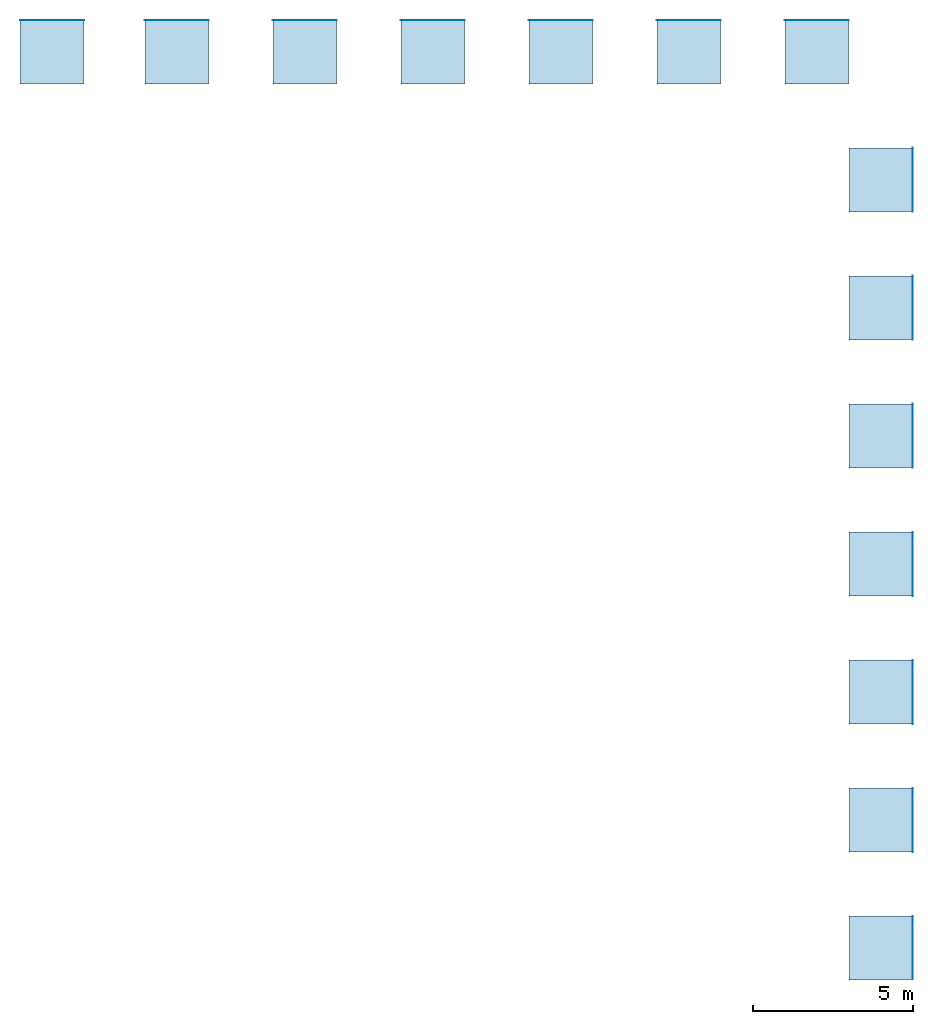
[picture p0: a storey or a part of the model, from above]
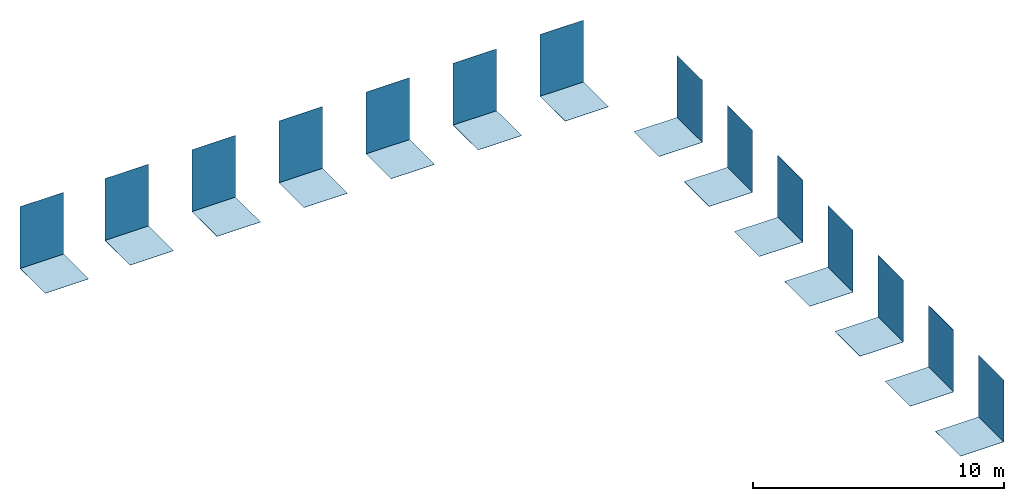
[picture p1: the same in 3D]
Properties of the parts of a building model (IFC2X3)

# File
Description: ViewDefinition [CoordinationView_V2.0]
File name: Project Number
Time: 2019-05-09T15:24:18
Written by: The EXPRESS Data Manager Version 5.02.0100.07 : 28 Aug 2013
Made in: 20181011_1645(x64) - Exporter 17.2.0.0 - Alternate UI 17.2.0.0
Comment: STEP Physical File produced by: The EXPRESS Data Manager Version 5.02.0100.07 : 28 Aug 2013 * Module: EDMstepFileFactory/EDMstandAlone * Creation date: Thu May 09 15:24:18 2019 * Host: aiepmoliner * Database: C:\Users\ES0050~1\AppData\Local\Temp\{F7FDD86A-AAB0-48F5-83BF-313EA6CE89DC}\ifc * Database version: 5507 * Database creation date: Thu May 09 15:24:14 2019 * Schema: IFC2X3 * Model: DataRepository.ifc * Model creation date: Thu May 09 15:24:15 2019 * Header model: DataRepository.ifc_HeaderModel * Header model creation date: Thu May 09 15:24:15 2019 * EDMuser: sdai-user * EDMgroup: sdai-group * License ID and type: 5605 : Permanent license. Expiry date: * EDMstepFileFactory options: 020000

# IfcProject, Project Number
LongName: Project Name; Phase: Project Status

# IfcSite, Default
RefLatitude: 42, 21, 31, 181945; RefLongitude: -71, -3, -24, -263305; RefElevation: 0 mm

# IfcBuildingStorey, Level 1
LongName: Level 1; Elevation: 0 mm

# IfcSlab: Floor:PGR_AnticColonial_WoodFibreBoards_Residence_Arizona-193x1380mm-100201388, Floor:PGR_AnticColonial_WoodFibreBoards_Residence_Arizona-193x1380mm-100201388:211493
In: Level 1
PredefinedType: FLOOR; Material: PGR_AnticColonial_WoodFibreBoards_Residence_Arizona-193x1380mm-100201388 8 mm

# IfcSlab: Floor:PGR_AnticColonial_WoodFibreBoards_Residence_Idaho-193x1380mm-100201389, Floor:PGR_AnticColonial_WoodFibreBoards_Residence_Idaho-193x1380mm-100201389:211503
In: Level 1
PredefinedType: FLOOR; Material: PGR_AnticColonial_WoodFibreBoards_Residence_Idaho-193x1380mm-100201389 8 mm

# IfcSlab: Floor:PGR_AnticColonial_WoodFibreBoards_Residence_Iowa-193x1380mm-100176300, Floor:PGR_AnticColonial_WoodFibreBoards_Residence_Iowa-193x1380mm-100176300:211553
In: Level 1
PredefinedType: FLOOR; Material: PGR_AnticColonial_WoodFibreBoards_Residence_Iowa-193x1380mm-100176300 8 mm

# IfcSlab: Floor:PGR_AnticColonial_WoodFibreBoards_Residence_Maine-193x1380mm-100176301, Floor:PGR_AnticColonial_WoodFibreBoards_Residence_Maine-193x1380mm-100176301:214856
In: Level 1
PredefinedType: FLOOR; Material: PGR_AnticColonial_WoodFibreBoards_Residence_Maine-193x1380mm-100176301 8 mm

# IfcSlab: Floor:PGR_AnticColonial_WoodFibreBoards_Residence_Misuri-193x1380mm-100201397, Floor:PGR_AnticColonial_WoodFibreBoards_Residence_Misuri-193x1380mm-100201397:211513
In: Level 1
PredefinedType: FLOOR; Material: PGR_AnticColonial_WoodFibreBoards_Residence_Misuri-193x1380mm-100201397 8 mm

# IfcSlab: Floor:PGR_AnticColonial_WoodFibreBoards_Residence_Nevada-193x1380mm-100201404, Floor:PGR_AnticColonial_WoodFibreBoards_Residence_Nevada-193x1380mm-100201404:211603
In: Level 1
PredefinedType: FLOOR; Material: PGR_AnticColonial_WoodFibreBoards_Residence_Nevada-193x1380mm-100201404 8 mm

# IfcSlab: Floor:PGR_AnticColonial_WoodFibreBoards_Residence_New_Jersey-193x1380mm-100176290, Floor:PGR_AnticColonial_WoodFibreBoards_Residence_New_Jersey-193x1380mm-100176290:211543
In: Level 1
PredefinedType: FLOOR; Material: PGR_AnticColonial_WoodFibreBoards_Residence_New_Jersey-193x1380mm-100176290 8 mm

# IfcSlab: Floor:PGR_AnticColonial_WoodFibreBoards_Residence_Nogal-193x1380mm-100202966, Floor:PGR_AnticColonial_WoodFibreBoards_Residence_Nogal-193x1380mm-100202966:211523
In: Level 1
PredefinedType: FLOOR; Material: PGR_AnticColonial_WoodFibreBoards_Residence_Nogal-193x1380mm-100202966 8 mm

# IfcSlab: Floor:PGR_AnticColonial_WoodFibreBoards_Residence_Ohio-193x1380mm-100175399, Floor:PGR_AnticColonial_WoodFibreBoards_Residence_Ohio-193x1380mm-100175399:211593
In: Level 1
PredefinedType: FLOOR; Material: PGR_AnticColonial_WoodFibreBoards_Residence_Ohio-193x1380mm-100175399 8 mm

# IfcSlab: Floor:PGR_AnticColonial_WoodFibreBoards_Residence_Roble-193x1380mm-100176291, Floor:PGR_AnticColonial_WoodFibreBoards_Residence_Roble-193x1380mm-100176291:211563
In: Level 1
PredefinedType: FLOOR; Material: PGR_AnticColonial_WoodFibreBoards_Residence_Roble-193x1380mm-100176291 8 mm

# IfcSlab: Floor:PGR_AnticColonial_WoodFibreBoards_Residence_Roble_Decape-193x1380mm-100176288, Floor:PGR_AnticColonial_WoodFibreBoards_Residence_Roble_Decape-193x1380mm-100176288:202324
In: Level 1
PredefinedType: FLOOR; Material: PGR_AnticColonial_WoodFibreBoards_Residence_Roble_Decape-193x1380mm-100176288 8 mm

# IfcSlab: Floor:PGR_AnticColonial_WoodFibreBoards_Residence_Utah-193x1380mm-100201410, Floor:PGR_AnticColonial_WoodFibreBoards_Residence_Utah-193x1380mm-100201410:211533
In: Level 1
PredefinedType: FLOOR; Material: PGR_AnticColonial_WoodFibreBoards_Residence_Utah-193x1380mm-100201410 8 mm

# IfcSlab: Floor:PGR_AnticColonial_WoodFibreBoards_Residence_Vermont-193x1380mm-100176289, Floor:PGR_AnticColonial_WoodFibreBoards_Residence_Vermont-193x1380mm-100176289:211573
In: Level 1
PredefinedType: FLOOR; Material: PGR_AnticColonial_WoodFibreBoards_Residence_Vermont-193x1380mm-100176289 8 mm

# IfcSlab: Floor:PGR_AnticColonial_WoodFibreBoards_Residence_Virginia-193x1380mm-100175398, Floor:PGR_AnticColonial_WoodFibreBoards_Residence_Virginia-193x1380mm-100175398:211583
In: Level 1
PredefinedType: FLOOR; Material: PGR_AnticColonial_WoodFibreBoards_Residence_Virginia-193x1380mm-100175398 8 mm

# IfcWallStandardCase: Basic Wall:PGR_AnticColonial_WoodFibreBoards_Residence_Arizona-193x1380mm-100201388, Basic Wall:PGR_AnticColonial_WoodFibreBoards_Residence_Arizona-193x1380mm-100201388:211498
In: Level 1
Type - PredefinedType: STANDARD; Material: PGR_AnticColonial_WoodFibreBoards_Residence_Arizona-193x1380mm-100201388 8 mm
Type - NBS_General - Author: Porcelanosa Group; BIMObjectName: PGR_AnticColonial_WoodFibreBoards_Residence_Arizona_193x1380mm-100201388; ManufacturerURL: www.anticcolonial.com; NBSDescription: Wood laminate strips and boards; NBSReference: 45-45-95/370; ProductInformation: http://calidad.info-grupo.com:8081/GeneraFicha3/PDF?articulo=100201388&lang=EN&un=0; Revision: n/a; Uniclass2015Code: Pr_25_71_97_92; Uniclass2015Title: Wood fibre boards; Uniclass2015Version: V1_9; Version: 1
Type - COBie - AccessibilityPerformance: See ProductInformation for technical PDF; AssetType: Fixed; Category: Walls; CodePerformance: FSC; Color: Gray; Constituents: n/a; Description: Laminate flooring, RESIDENCE collection from L'ANTIC COLONIAL (Porcelanosa Group), ROBLE DECAPE model and LIFE finish, 19,3x138 cm. (8mm thickness), Class 23/32, abrasion resistance AC4, formed by high density fiber board and water-repellent glues.; DurationUnit: year; ExpectedLife: n/a; Features: See ProductInformation for technical PDF; Grade: n/a; Manufacturer: bim.gp@porcelanosagrupo.com; ModelNumber: 100201388; ModelReference: AC4 RESIDENCE 1L ARIZONA 19,3X138X0,8; Name: WoodFibreBoards_Residence_Arizona_193x1380mm-100201388; ReplacementCost: n/a; Shape: Rectangular; Size: 193x1380x8mm; Sustainability Performance: See ProductInformation for technical PDF; WarrantyDescription: Manufacturer warranty, applicable worldwide, with the pertinent national legislation prevailing in all cases; all products must have been manufactured and fitted in accordance with the Fabricator's Manual, and have been used and cared for in accordance with the Guide to Use, Cleaning and Care available on the web page www.porcelanosa.com; WarrantyDurationLabor: n/a; WarrantyDurationParts: 20; WarrantyDurationUnit: year; WarrantyGuarantorLabor: n/a; WarrantyGuarantorParts: bim.gp@porcelanosagrupo.com
Type - Pset_CoveringCommon - IsExternal: no; Reference: -; AcousticRating: n/a; Finish: Life; FireRating: Cfl-s1; FlammabilityRating: n/a; FragilityRating: n/a; Material: High-density fibreboard; SurfaceSpreadOfFlame: n/a; ThermalTransmittance: 287.5 kg/K/s3; TotalThickness: 8 mm
Type - IFC - IfcExportAS: IfcCoveringType; IfcExportType: Flooring
Type - NBS_Data - AbrasionResistance: AC4; Collection: Residence; CreationDate: 2018/09; SlipResistanceValuePendulumTestValue: Class DS; StainResistance: Grade 5 (G 1 and 2) and Grade 4 (G 3)
COBie - AssetIdentifier: n/a; BarCode: n/a; InstallationDate: 1900-12-31T23:59:59; TagNumber: n/a; WarrantyStartDate: 1900-12-31T23:59:59

# IfcWallStandardCase: Basic Wall:PGR_AnticColonial_WoodFibreBoards_Residence_Idaho-193x1380mm-100201389, Basic Wall:PGR_AnticColonial_WoodFibreBoards_Residence_Idaho-193x1380mm-100201389:211508
In: Level 1
Type - PredefinedType: STANDARD; Material: PGR_AnticColonial_WoodFibreBoards_Residence_Idaho-193x1380mm-100201389 8 mm
Type - NBS_General - Author: Porcelanosa Group; BIMObjectName: PGR_AnticColonial_WoodFibreBoards_Residence_Idaho_193x1380mm-100201389; ManufacturerURL: www.anticcolonial.com; NBSDescription: Wood laminate strips and boards; NBSReference: 45-45-95/370; ProductInformation: http://calidad.info-grupo.com:8081/GeneraFicha3/PDF?articulo=100201389&lang=EN&un=0; Revision: n/a; Uniclass2015Code: Pr_25_71_97_92; Uniclass2015Title: Wood fibre boards; Uniclass2015Version: V1_9; Version: 1
Type - COBie - AccessibilityPerformance: See ProductInformation for technical PDF; AssetType: Fixed; Category: Walls; CodePerformance: FSC; Color: Brown; Constituents: n/a; Description: Laminate flooring, RESIDENCE collection from L'ANTIC COLONIAL (Porcelanosa Group), ROBLE DECAPE model and LIFE finish, 19,3x138 cm. (8mm thickness), Class 23/32, abrasion resistance AC4, formed by high density fiber board and water-repellent glues.; DurationUnit: year; ExpectedLife: n/a; Features: See ProductInformation for technical PDF; Grade: n/a; Manufacturer: bim.gp@porcelanosagrupo.com; ModelNumber: 100201389; ModelReference: AC4 RESIDENCE 1L IDAHO 19,3X138X0,8; Name: WoodFibreBoards_Residence_Idaho_193x1380mm-100201389; ReplacementCost: n/a; Shape: Rectangular; Size: 193x1380x8mm; Sustainability Performance: See ProductInformation for technical PDF; WarrantyDescription: Manufacturer warranty, applicable worldwide, with the pertinent national legislation prevailing in all cases; all products must have been manufactured and fitted in accordance with the Fabricator's Manual, and have been used and cared for in accordance with the Guide to Use, Cleaning and Care available on the web page www.porcelanosa.com; WarrantyDurationLabor: n/a; WarrantyDurationParts: 20; WarrantyDurationUnit: year; WarrantyGuarantorLabor: n/a; WarrantyGuarantorParts: bim.gp@porcelanosagrupo.com
Type - Pset_CoveringCommon - IsExternal: no; Reference: -; AcousticRating: n/a; Finish: Life; FireRating: Cfl-s1; FlammabilityRating: n/a; FragilityRating: n/a; Material: High-density fibreboard; SurfaceSpreadOfFlame: n/a; ThermalTransmittance: 287.5 kg/K/s3; TotalThickness: 8 mm
Type - IFC - IfcExportAS: IfcCoveringType; IfcExportType: Flooring
Type - NBS_Data - AbrasionResistance: AC4; Collection: Residence; CreationDate: 2018/09; SlipResistanceValuePendulumTestValue: Class DS; StainResistance: Grade 5 (G 1 and 2) and Grade 4 (G 3)
COBie - AssetIdentifier: n/a; BarCode: n/a; InstallationDate: 1900-12-31T23:59:59; TagNumber: n/a; WarrantyStartDate: 1900-12-31T23:59:59

# IfcWallStandardCase: Basic Wall:PGR_AnticColonial_WoodFibreBoards_Residence_Iowa-193x1380mm-100176300, Basic Wall:PGR_AnticColonial_WoodFibreBoards_Residence_Iowa-193x1380mm-100176300:211558
In: Level 1
Type - PredefinedType: STANDARD; Material: PGR_AnticColonial_WoodFibreBoards_Residence_Iowa-193x1380mm-100176300 8 mm
Type - NBS_General - Author: Porcelanosa Group; BIMObjectName: PGR_AnticColonial_WoodFibreBoards_Residence_Iowa_193x1380mm-100176300; ManufacturerURL: www.anticcolonial.com; NBSDescription: Wood laminate strips and boards; NBSReference: 45-45-95/370; ProductInformation: http://calidad.info-grupo.com:8081/GeneraFicha3/PDF?articulo=100176300&lang=EN&un=0; Revision: n/a; Uniclass2015Code: Pr_25_71_97_92; Uniclass2015Title: Wood fibre boards; Uniclass2015Version: V1_9; Version: 1
Type - COBie - AccessibilityPerformance: See ProductInformation for technical PDF; AssetType: Fixed; Category: Walls; CodePerformance: FSC; Color: Walnut; Constituents: n/a; Description: Laminate flooring, RESIDENCE collection from L'ANTIC COLONIAL (Porcelanosa Group), ROBLE DECAPE model and LIFE finish, 19,3x138 cm. (8mm thickness), Class 23/32, abrasion resistance AC4, formed by high density fiber board and water-repellent glues.; DurationUnit: year; ExpectedLife: n/a; Features: See ProductInformation for technical PDF; Grade: n/a; Manufacturer: bim.gp@porcelanosagrupo.com; ModelNumber: 100176300; ModelReference: AC4 RESIDENCE ANTI 2L IOWA 19,3X138X0,8; Name: WoodFibreBoards_Residence_Iowa_193x1380mm-100176300; ReplacementCost: n/a; Shape: Rectangular; Size: 193x1380x8mm; Sustainability Performance: See ProductInformation for technical PDF; WarrantyDescription: Manufacturer warranty, applicable worldwide, with the pertinent national legislation prevailing in all cases; all products must have been manufactured and fitted in accordance with the Fabricator's Manual, and have been used and cared for in accordance with the Guide to Use, Cleaning and Care available on the web page www.porcelanosa.com; WarrantyDurationLabor: n/a; WarrantyDurationParts: 20; WarrantyDurationUnit: year; WarrantyGuarantorLabor: n/a; WarrantyGuarantorParts: bim.gp@porcelanosagrupo.com
Type - Pset_CoveringCommon - IsExternal: no; Reference: -; AcousticRating: n/a; Finish: Life; FireRating: Cfl-s1; FlammabilityRating: n/a; FragilityRating: n/a; Material: High-density fibreboard; SurfaceSpreadOfFlame: n/a; ThermalTransmittance: 287.5 kg/K/s3; TotalThickness: 8 mm
Type - IFC - IfcExportAS: IfcCoveringType; IfcExportType: Flooring
Type - NBS_Data - AbrasionResistance: AC4; Collection: Residence; CreationDate: 2018/09; SlipResistanceValuePendulumTestValue: Class DS; StainResistance: Grade 5 (G 1 and 2) and Grade 4 (G 3)
COBie - AssetIdentifier: n/a; BarCode: n/a; InstallationDate: 1900-12-31T23:59:59; TagNumber: n/a; WarrantyStartDate: 1900-12-31T23:59:59

# IfcWallStandardCase: Basic Wall:PGR_AnticColonial_WoodFibreBoards_Residence_Maine-193x1380mm-100176301, Basic Wall:PGR_AnticColonial_WoodFibreBoards_Residence_Maine-193x1380mm-100176301:214861
In: Level 1
Type - PredefinedType: STANDARD; Material: PGR_AnticColonial_WoodFibreBoards_Residence_Maine-193x1380mm-100176301 8 mm
Type - NBS_General - Author: Porcelanosa Group; BIMObjectName: PGR_AnticColonial_WoodFibreBoards_Residence_Maine_193x1380mm-100201404; ManufacturerURL: www.anticcolonial.com; NBSDescription: Wood laminate strips and boards; NBSReference: 45-45-95/370; ProductInformation: http://calidad.info-grupo.com:8081/GeneraFicha3/PDF?articulo=100176301&lang=EN&un=0; Revision: n/a; Uniclass2015Code: Pr_25_71_97_92; Uniclass2015Title: Wood fibre boards; Uniclass2015Version: V1_9; Version: 1
Type - COBie - AccessibilityPerformance: See ProductInformation for technical PDF; AssetType: Fixed; Category: Pr_25_71_97_92: Wood Fibre Boards; CodePerformance: FSC; Color: Natural; Constituents: n/a; Description: Laminate flooring, RESIDENCE collection from L'ANTIC COLONIAL (Porcelanosa Group), ROBLE DECAPE model and LIFE finish, 19,3x138 cm. (8mm thickness), Class 23/32, abrasion resistance AC4, formed by high density fiber board and water-repellent glues.; DurationUnit: year; ExpectedLife: n/a; Features: See ProductInformation for technical PDF; Grade: n/a; Manufacturer: bim.gp@porcelanosagrupo.com; ModelNumber: 100176301; ModelReference: AC4 RESIDENCE 2L MAINE 19,3X138X0,8; Name: WoodFibreBoards_Residence_Maine_193x1380mm-100201404; ReplacementCost: n/a; Shape: Rectangular; Size: 193x1380x8mm; Sustainability Performance: See ProductInformation for technical PDF; WarrantyDescription: Manufacturer warranty, applicable worldwide, with the pertinent national legislation prevailing in all cases; all products must have been manufactured and fitted in accordance with the Fabricator's Manual, and have been used and cared for in accordance with the Guide to Use, Cleaning and Care available on the web page www.porcelanosa.com; WarrantyDurationLabor: n/a; WarrantyDurationParts: 20; WarrantyDurationUnit: year; WarrantyGuarantorLabor: n/a; WarrantyGuarantorParts: bim.gp@porcelanosagrupo.com
Type - Pset_CoveringCommon - IsExternal: no; Reference: -; AcousticRating: n/a; Finish: Life; FireRating: Cfl-s1; FlammabilityRating: n/a; FragilityRating: n/a; Material: High-density fibreboard; SurfaceSpreadOfFlame: n/a; ThermalTransmittance: 287.5 kg/K/s3; TotalThickness: 8 mm
Type - IFC - IfcExportAS: IfcCoveringType; IfcExportType: Flooring
Type - NBS_Data - AbrasionResistance: AC4; Collection: Residence; CreationDate: 2019/05; SlipResistanceValuePendulumTestValue: Class DS; StainResistance: Grade 5 (G 1 and 2) and Grade 4 (G 3)
COBie - AssetIdentifier: n/a; BarCode: n/a; InstallationDate: 1900-12-31T23:59:59; TagNumber: n/a; WarrantyStartDate: 1900-12-31T23:59:59

# IfcWallStandardCase: Basic Wall:PGR_AnticColonial_WoodFibreBoards_Residence_Misuri-193x1380mm-100201397 (2)
In: Level 1
Type - PredefinedType: STANDARD; Material: PGR_AnticColonial_WoodFibreBoards_Residence_Misuri-193x1380mm-100201397 8 mm
Type - NBS_General - Author: Porcelanosa Group; BIMObjectName: PGR_AnticColonial_WoodFibreBoards_Residence_Nevada_193x1380mm-100201404; ManufacturerURL: www.anticcolonial.com; NBSDescription: Wood laminate strips and boards; NBSReference: 45-45-95/370; ProductInformation: http://calidad.info-grupo.com:8081/GeneraFicha3/PDF?articulo=100201404&lang=EN&un=0; Revision: n/a; Uniclass2015Code: Pr_25_71_97_92; Uniclass2015Title: Wood fibre boards; Uniclass2015Version: V1_9; Version: 1
Type - COBie - AccessibilityPerformance: See ProductInformation for technical PDF; AssetType: Fixed; Category: Pr_25_71_97_92: Wood Fibre Boards; CodePerformance: FSC; Color: Brown; Constituents: n/a; Description: Laminate flooring, RESIDENCE collection from L'ANTIC COLONIAL (Porcelanosa Group), ROBLE DECAPE model and LIFE finish, 19,3x138 cm. (8mm thickness), Class 23/32, abrasion resistance AC4, formed by high density fiber board and water-repellent glues.; DurationUnit: year; ExpectedLife: n/a; Features: See ProductInformation for technical PDF; Grade: n/a; Manufacturer: bim.gp@porcelanosagrupo.com; ModelNumber: 100201404; ModelReference: AC4 RESIDENCE 1L NEVADA 19,3X138X0,8; Name: WoodFibreBoards_Residence_Nevada_193x1380mm-100201404; ReplacementCost: n/a; Shape: Rectangular; Size: 193x1380x8mm; Sustainability Performance: See ProductInformation for technical PDF; WarrantyDescription: Manufacturer warranty, applicable worldwide, with the pertinent national legislation prevailing in all cases; all products must have been manufactured and fitted in accordance with the Fabricator's Manual, and have been used and cared for in accordance with the Guide to Use, Cleaning and Care available on the web page www.porcelanosa.com; WarrantyDurationLabor: n/a; WarrantyDurationParts: 20; WarrantyDurationUnit: year; WarrantyGuarantorLabor: n/a; WarrantyGuarantorParts: bim.gp@porcelanosagrupo.com
Type - Pset_CoveringCommon - IsExternal: no; Reference: -; AcousticRating: n/a; Finish: Life; FireRating: Cfl-s1; FlammabilityRating: n/a; FragilityRating: n/a; Material: High-density fibreboard; SurfaceSpreadOfFlame: n/a; ThermalTransmittance: 287.5 kg/K/s3; TotalThickness: 8 mm
Type - IFC - IfcExportAS: IfcCoveringType; IfcExportType: Flooring
Type - NBS_Data - AbrasionResistance: AC4; Collection: Residence; CreationDate: 2018/09; SlipResistanceValuePendulumTestValue: Class DS; StainResistance: Grade 5 (G 1 and 2) and Grade 4 (G 3)
COBie - AssetIdentifier: n/a; BarCode: n/a; InstallationDate: 1900-12-31T23:59:59; TagNumber: n/a; WarrantyStartDate: 1900-12-31T23:59:59
Name (Basic Wall:PGR_AnticColonial_WoodFibreBoards_Residence_Misuri-193x1380mm-100201397:...)
211518
212001

# IfcWallStandardCase: Basic Wall:PGR_AnticColonial_WoodFibreBoards_Residence_Nevada-193x1380mm-100201404, Basic Wall:PGR_AnticColonial_WoodFibreBoards_Residence_Nevada-193x1380mm-100201404:211608
In: Level 1
Type - PredefinedType: STANDARD; Material: PGR_AnticColonial_WoodFibreBoards_Residence_Nevada-193x1380mm-100201404 8 mm
Type - NBS_General - Author: Porcelanosa Group; BIMObjectName: PGR_AnticColonial_WoodFibreBoards_Residence_Utah_193x1380mm-100201410; ManufacturerURL: www.anticcolonial.com; NBSDescription: Wood laminate strips and boards; NBSReference: 45-45-95/370; ProductInformation: http://calidad.info-grupo.com:8081/GeneraFicha3/PDF?articulo=100201410&lang=EN&un=0; Revision: n/a; Uniclass2015Code: Pr_25_71_97_92; Uniclass2015Title: Wood fibre boards; Uniclass2015Version: V1_9; Version: 1
Type - COBie - AccessibilityPerformance: See ProductInformation for technical PDF; AssetType: Fixed; Category: Pr_25_71_97_92: Wood Fibre Boards; CodePerformance: FSC; Color: Brown; Constituents: n/a; Description: Laminate flooring, RESIDENCE collection from L'ANTIC COLONIAL (Porcelanosa Group), ROBLE DECAPE model and LIFE finish, 19,3x138 cm. (8mm thickness), Class 23/32, abrasion resistance AC4, formed by high density fiber board and water-repellent glues.; DurationUnit: year; ExpectedLife: n/a; Features: See ProductInformation for technical PDF; Grade: n/a; Manufacturer: bim.gp@porcelanosagrupo.com; ModelNumber: 100201410; ModelReference: AC4 RESIDENCE 1L UTAH 19,3X138X0,8; Name: WoodFibreBoards_Residence_Utah_193x1380mm-100201410; ReplacementCost: n/a; Shape: Rectangular; Size: 193x1380x8mm; Sustainability Performance: See ProductInformation for technical PDF; WarrantyDescription: Manufacturer warranty, applicable worldwide, with the pertinent national legislation prevailing in all cases; all products must have been manufactured and fitted in accordance with the Fabricator's Manual, and have been used and cared for in accordance with the Guide to Use, Cleaning and Care available on the web page www.porcelanosa.com; WarrantyDurationLabor: n/a; WarrantyDurationParts: 20; WarrantyDurationUnit: year; WarrantyGuarantorLabor: n/a; WarrantyGuarantorParts: bim.gp@porcelanosagrupo.com
Type - Pset_CoveringCommon - IsExternal: no; Reference: -; AcousticRating: n/a; Finish: Life; FireRating: Cfl-s1; FlammabilityRating: n/a; FragilityRating: n/a; Material: High-density fibreboard; SurfaceSpreadOfFlame: n/a; ThermalTransmittance: 287.5 kg/K/s3; TotalThickness: 8 mm
Type - IFC - IfcExportAS: IfcCoveringType; IfcExportType: Flooring
Type - NBS_Data - AbrasionResistance: AC4; Collection: Residence; CreationDate: 2018/09; SlipResistanceValuePendulumTestValue: Class DS; StainResistance: Grade 5 (G 1 and 2) and Grade 4 (G 3)
COBie - AssetIdentifier: n/a; BarCode: n/a; InstallationDate: 1900-12-31T23:59:59; TagNumber: n/a; WarrantyStartDate: 1900-12-31T23:59:59

# IfcWallStandardCase: Basic Wall:PGR_AnticColonial_WoodFibreBoards_Residence_New_Jersey-193x1380mm-100176290, Basic Wall:PGR_AnticColonial_WoodFibreBoards_Residence_New_Jersey-193x1380mm-100176290:211548
In: Level 1
Type - PredefinedType: STANDARD; Material: PGR_AnticColonial_WoodFibreBoards_Residence_New_Jersey-193x1380mm-100176290 8 mm
Type - NBS_General - Author: Porcelanosa Group; BIMObjectName: PGR_AnticColonial_WoodFibreBoards_Residence_NewJersey_193x1380mm-100176290; ManufacturerURL: www.anticcolonial.com; NBSDescription: Wood laminate strips and boards; NBSReference: 45-45-95/370; ProductInformation: http://calidad.info-grupo.com:8081/GeneraFicha3/PDF?articulo=100176290&lang=EN&un=0; Revision: n/a; Uniclass2015Code: Pr_25_71_97_92; Uniclass2015Title: Wood fibre boards; Uniclass2015Version: V1_9; Version: 1
Type - COBie - AccessibilityPerformance: See ProductInformation for technical PDF; AssetType: Fixed; Category: Pr_25_71_97_92: Wood Fibre Boards; CodePerformance: FSC; Color: Brown; Constituents: n/a; Description: Laminate flooring, RESIDENCE collection from L'ANTIC COLONIAL (Porcelanosa Group), ROBLE DECAPE model and LIFE finish, 19,3x138 cm. (8mm thickness), Class 23/32, abrasion resistance AC4, formed by high density fiber board and water-repellent glues.; DurationUnit: year; ExpectedLife: n/a; Features: See ProductInformation for technical PDF; Grade: n/a; Manufacturer: bim.gp@porcelanosagrupo.com; ModelNumber: 100176290; ModelReference: AC4 RESIDENCE ANTI 1L NEW JERSEY 19,3X138X0,8; Name: WoodFibreBoards_Residence_NewJersey_193x1380mm-100176290; ReplacementCost: n/a; Shape: Rectangular; Size: 193x1380x8mm; Sustainability Performance: See ProductInformation for technical PDF; WarrantyDescription: Manufacturer warranty, applicable worldwide, with the pertinent national legislation prevailing in all cases; all products must have been manufactured and fitted in accordance with the Fabricator's Manual, and have been used and cared for in accordance with the Guide to Use, Cleaning and Care available on the web page www.porcelanosa.com; WarrantyDurationLabor: n/a; WarrantyDurationParts: 20; WarrantyDurationUnit: year; WarrantyGuarantorLabor: n/a; WarrantyGuarantorParts: bim.gp@porcelanosagrupo.com
Type - Pset_CoveringCommon - IsExternal: no; Reference: -; AcousticRating: n/a; Finish: Life; FireRating: Cfl-s1; FlammabilityRating: n/a; FragilityRating: n/a; Material: High-density fibreboard; SurfaceSpreadOfFlame: n/a; ThermalTransmittance: 287.5 kg/K/s3; TotalThickness: 8 mm
Type - IFC - IfcExportAS: IfcCoveringType; IfcExportType: Flooring
Type - NBS_Data - AbrasionResistance: AC4; Collection: Residence; CreationDate: 2018/09; SlipResistanceValuePendulumTestValue: Class DS; StainResistance: Grade 5 (G 1 and 2) and Grade 4 (G 3)
COBie - AssetIdentifier: n/a; BarCode: n/a; InstallationDate: 1900-12-31T23:59:59; TagNumber: n/a; WarrantyStartDate: 1900-12-31T23:59:59

# IfcWallStandardCase: Basic Wall:PGR_AnticColonial_WoodFibreBoards_Residence_Nogal-193x1380mm-100202966, Basic Wall:PGR_AnticColonial_WoodFibreBoards_Residence_Nogal-193x1380mm-100202966:211528
In: Level 1
Type - PredefinedType: STANDARD; Material: PGR_AnticColonial_WoodFibreBoards_Residence_Nogal-193x1380mm-100202966 8 mm
Type - NBS_General - Author: Porcelanosa Group; BIMObjectName: PGR_AnticColonial_WoodFibreBoards_Residence_Nogal_193x1380mm-100202966; ManufacturerURL: www.anticcolonial.com; NBSDescription: Wood laminate strips and boards; NBSReference: 45-45-95/370; ProductInformation: http://calidad.info-grupo.com:8081/GeneraFicha3/PDF?articulo=100202966&lang=EN&un=0; Revision: n/a; Uniclass2015Code: Pr_25_71_97_92; Uniclass2015Title: Wood fibre boards; Uniclass2015Version: V1_9; Version: 1
Type - COBie - AccessibilityPerformance: See ProductInformation for technical PDF; AssetType: Fixed; Category: Pr_25_71_97_92: Wood Fibre Boards; CodePerformance: FSC; Color: Walnut; Constituents: n/a; Description: Laminate flooring, RESIDENCE collection from L'ANTIC COLONIAL (Porcelanosa Group), ROBLE DECAPE model and LIFE finish, 19,3x138 cm. (8mm thickness), Class 23/32, abrasion resistance AC4, formed by high density fiber board and water-repellent glues.; DurationUnit: year; ExpectedLife: n/a; Features: See ProductInformation for technical PDF; Grade: n/a; Manufacturer: bim.gp@porcelanosagrupo.com; ModelNumber: 100202966; ModelReference: AC4 RESIDENCE ANTI 1L NOGAL 19,3X138X0,8; Name: WoodFibreBoards_Residence_Nogal_193x1380mm-100202966; ReplacementCost: n/a; Shape: Rectangular; Size: 193x1380x8mm; Sustainability Performance: See ProductInformation for technical PDF; WarrantyDescription: Manufacturer warranty, applicable worldwide, with the pertinent national legislation prevailing in all cases; all products must have been manufactured and fitted in accordance with the Fabricator's Manual, and have been used and cared for in accordance with the Guide to Use, Cleaning and Care available on the web page www.porcelanosa.com; WarrantyDurationLabor: n/a; WarrantyDurationParts: 20; WarrantyDurationUnit: year; WarrantyGuarantorLabor: n/a; WarrantyGuarantorParts: bim.gp@porcelanosagrupo.com
Type - Pset_CoveringCommon - IsExternal: no; Reference: -; AcousticRating: n/a; Finish: Life; FireRating: Cfl-s1; FlammabilityRating: n/a; FragilityRating: n/a; Material: High-density fibreboard; SurfaceSpreadOfFlame: n/a; ThermalTransmittance: 287.5 kg/K/s3; TotalThickness: 8 mm
Type - IFC - IfcExportAS: IfcCoveringType; IfcExportType: Flooring
Type - NBS_Data - AbrasionResistance: AC4; Collection: Residence; CreationDate: 2018/09; SlipResistanceValuePendulumTestValue: Class DS; StainResistance: Grade 5 (G 1 and 2) and Grade 4 (G 3)
COBie - AssetIdentifier: n/a; BarCode: n/a; InstallationDate: 1900-12-31T23:59:59; TagNumber: n/a; WarrantyStartDate: 1900-12-31T23:59:59

# IfcWallStandardCase: Basic Wall:PGR_AnticColonial_WoodFibreBoards_Residence_Ohio-193x1380mm-100175399, Basic Wall:PGR_AnticColonial_WoodFibreBoards_Residence_Ohio-193x1380mm-100175399:211598
In: Level 1
Type - PredefinedType: STANDARD; Material: PGR_AnticColonial_WoodFibreBoards_Residence_Ohio-193x1380mm-100175399 8 mm
Type - NBS_General - Author: Porcelanosa Group; BIMObjectName: PGR_AnticColonial_WoodFibreBoards_Residence_Ohio_193x1380mm-100175399; ManufacturerURL: www.anticcolonial.com; NBSDescription: Wood laminate strips and boards; NBSReference: 45-45-95/370; ProductInformation: http://calidad.info-grupo.com:8081/GeneraFicha3/PDF?articulo=100175399&lang=EN&un=0; Revision: n/a; Uniclass2015Code: Pr_25_71_97_92; Uniclass2015Title: Wood fibre boards; Uniclass2015Version: V1_9; Version: 1
Type - COBie - AccessibilityPerformance: See ProductInformation for technical PDF; AssetType: Fixed; Category: Pr_25_71_97_92: Wood Fibre Boards; CodePerformance: FSC; Color: Gray; Constituents: n/a; Description: Laminate flooring, RESIDENCE collection from L'ANTIC COLONIAL (Porcelanosa Group), ROBLE DECAPE model and NATURAL finish, 19,3x138 cm. (8mm thickness), Class 23/32, abrasion resistance AC4, formed by high density fiber board and water-repellent glues.; DurationUnit: year; ExpectedLife: n/a; Features: See ProductInformation for technical PDF; Grade: n/a; Manufacturer: bim.gp@porcelanosagrupo.com; ModelNumber: 100175399; ModelReference: AC4 RESIDENCE ANTI 3L OHIO 19,3X138X0,8; Name: WoodFibreBoards_Residence_Ohio_193x1380mm-100175399; ReplacementCost: n/a; Shape: Rectangular; Size: 193x1380x8mm; Sustainability Performance: See ProductInformation for technical PDF; WarrantyDescription: Manufacturer warranty, applicable worldwide, with the pertinent national legislation prevailing in all cases; all products must have been manufactured and fitted in accordance with the Fabricator's Manual, and have been used and cared for in accordance with the Guide to Use, Cleaning and Care available on the web page www.porcelanosa.com; WarrantyDurationLabor: n/a; WarrantyDurationParts: 20; WarrantyDurationUnit: year; WarrantyGuarantorLabor: n/a; WarrantyGuarantorParts: bim.gp@porcelanosagrupo.com
Type - Pset_CoveringCommon - IsExternal: no; Reference: -; AcousticRating: n/a; Finish: Natural; FireRating: Cfl-s1; FlammabilityRating: n/a; FragilityRating: n/a; Material: High-density fibreboard; SurfaceSpreadOfFlame: n/a; ThermalTransmittance: 287.5 kg/K/s3; TotalThickness: 8 mm
Type - IFC - IfcExportAS: IfcCoveringType; IfcExportType: Flooring
Type - NBS_Data - AbrasionResistance: AC4; Collection: Residence; CreationDate: 2018/09; SlipResistanceValuePendulumTestValue: Class DS; StainResistance: Grade 5 (G 1 and 2) and Grade 4 (G 3)
COBie - AssetIdentifier: n/a; BarCode: n/a; InstallationDate: 1900-12-31T23:59:59; TagNumber: n/a; WarrantyStartDate: 1900-12-31T23:59:59

# IfcWallStandardCase: Basic Wall:PGR_AnticColonial_WoodFibreBoards_Residence_Roble-193x1380mm-100176291, Basic Wall:PGR_AnticColonial_WoodFibreBoards_Residence_Roble-193x1380mm-100176291:211568
In: Level 1
Type - PredefinedType: STANDARD; Material: PGR_AnticColonial_WoodFibreBoards_Residence_Roble-193x1380mm-100176291 8 mm
Type - NBS_General - Author: Porcelanosa Group; BIMObjectName: PGR_AnticColonial_WoodFibreBoards_Residence_Roble_193x1380mm-100176291; ManufacturerURL: www.anticcolonial.com; NBSDescription: Wood laminate strips and boards; NBSReference: 45-45-95/370; ProductInformation: http://calidad.info-grupo.com:8081/GeneraFicha3/PDF?articulo=100176291&lang=EN&un=0; Revision: n/a; Uniclass2015Code: Pr_25_71_97_92; Uniclass2015Title: Wood fibre boards; Uniclass2015Version: V1_9; Version: 1
Type - COBie - AccessibilityPerformance: See ProductInformation for technical PDF; AssetType: Fixed; Category: Pr_25_71_97_92: Wood Fibre Boards; CodePerformance: FSC; Color: Natural; Constituents: n/a; Description: Laminate flooring, RESIDENCE collection from L'ANTIC COLONIAL (Porcelanosa Group), ROBLE DECAPE model and LIFE finish, 19,3x138 cm. (8mm thickness), Class 23/32, abrasion resistance AC4, formed by high density fiber board and water-repellent glues.; DurationUnit: year; ExpectedLife: n/a; Features: See ProductInformation for technical PDF; Grade: n/a; Manufacturer: bim.gp@porcelanosagrupo.com; ModelNumber: 100176291; ModelReference: AC4 RESIDENCE ANTI 1L ROBLE 19,3X138X0,8; Name: WoodFibreBoards_Residence_Roble_193x1380mm-100176291; ReplacementCost: n/a; Shape: Rectangular; Size: 193x1380x8mm; Sustainability Performance: See ProductInformation for technical PDF; WarrantyDescription: Manufacturer warranty, applicable worldwide, with the pertinent national legislation prevailing in all cases; all products must have been manufactured and fitted in accordance with the Fabricator's Manual, and have been used and cared for in accordance with the Guide to Use, Cleaning and Care available on the web page www.porcelanosa.com; WarrantyDurationLabor: n/a; WarrantyDurationParts: 20; WarrantyDurationUnit: year; WarrantyGuarantorLabor: n/a; WarrantyGuarantorParts: bim.gp@porcelanosagrupo.com
Type - Pset_CoveringCommon - IsExternal: no; Reference: -; AcousticRating: n/a; Finish: Life; FireRating: Cfl-s1; FlammabilityRating: n/a; FragilityRating: n/a; Material: High-density fibreboard; SurfaceSpreadOfFlame: n/a; ThermalTransmittance: 287.5 kg/K/s3; TotalThickness: 8 mm
Type - IFC - IfcExportAS: IfcCoveringType; IfcExportType: Flooring
Type - NBS_Data - AbrasionResistance: AC4; Collection: Residence; CreationDate: 2018/09; SlipResistanceValuePendulumTestValue: Class DS; StainResistance: Grade 5 (G 1 and 2) and Grade 4 (G 3)
COBie - AssetIdentifier: n/a; BarCode: n/a; InstallationDate: 1900-12-31T23:59:59; TagNumber: n/a; WarrantyStartDate: 1900-12-31T23:59:59

# IfcWallStandardCase: Basic Wall:PGR_AnticColonial_WoodFibreBoards_Residence_Roble_Decape-193x1380mm-100176288, Basic Wall:PGR_AnticColonial_WoodFibreBoards_Residence_Roble_Decape-193x1380mm-100176288:202329
In: Level 1
Type - PredefinedType: STANDARD; Material: PGR_AnticColonial_WoodFibreBoards_Residence_Roble_Decape-193x1380mm-100176288 8 mm
Type - NBS_General - Author: Porcelanosa Group; BIMObjectName: PGR_AnticColonial_WoodFibreBoards_Residence_RobleDecape_193x1380mm-100176288; ManufacturerURL: www.anticcolonial.com; NBSDescription: Wood laminate strips and boards; NBSReference: 45-45-95/370; ProductInformation: http://calidad.info-grupo.com:8081/GeneraFicha3/PDF?articulo=100176288&lang=EN&un=0; Revision: n/a; Uniclass2015Code: Pr_25_71_97_92; Uniclass2015Title: Wood fibre boards; Uniclass2015Version: V1_9; Version: 1
Type - COBie - AccessibilityPerformance: See ProductInformation for technical PDF; AssetType: Fixed; Category: Walls; CodePerformance: FSC; Color: Natural; Constituents: n/a; Description: Laminate flooring, RESIDENCE collection from L'ANTIC COLONIAL (Porcelanosa Group), ROBLE DECAPE model and LIFE finish, 19,3x138 cm. (8mm thickness), Class 23/32, abrasion resistance AC4, formed by high density fiber board and water-repellent glues.; DurationUnit: year; ExpectedLife: n/a; Features: See ProductInformation for technical PDF; Grade: n/a; Manufacturer: bim.gp@porcelanosagrupo.com; ModelNumber: 100176288; ModelReference: AC4 RESIDENCE ANTI 1L R. DECAPE 19,3X138X0,8; Name: WoodFibreBoards_Residence_RobleDecape_193x1380mm-100176288; ReplacementCost: n/a; Shape: Rectangular; Size: 193x1380x8mm; Sustainability Performance: See ProductInformation for technical PDF; WarrantyDescription: Manufacturer warranty, applicable worldwide, with the pertinent national legislation prevailing in all cases; all products must have been manufactured and fitted in accordance with the Fabricator's Manual, and have been used and cared for in accordance with the Guide to Use, Cleaning and Care available on the web page www.porcelanosa.com; WarrantyDurationLabor: n/a; WarrantyDurationParts: 20; WarrantyDurationUnit: year; WarrantyGuarantorLabor: n/a; WarrantyGuarantorParts: bim.gp@porcelanosagrupo.com
Type - Pset_CoveringCommon - AcousticRating: n/a; Finish: Life; FireRating: Cfl-s1; FlammabilityRating: n/a; FragilityRating: n/a; IsExternal: no; Material: High-density fibreboard; SurfaceSpreadOfFlame: n/a; ThermalTransmittance: 287.5 kg/K/s3; TotalThickness: 8 mm; Reference: -
Type - IFC - IfcExportAS: IfcCoveringType; IfcExportType: Flooring
Type - NBS_Data - AbrasionResistance: AC4; Collection: Residence; CreationDate: 2018/09; SlipResistanceValuePendulumTestValue: Class DS; StainResistance: Grade 5 (G 1 and 2) and Grade 4 (G 3)
COBie - AssetIdentifier: n/a; BarCode: n/a; InstallationDate: 1900-12-31T23:59:59; TagNumber: n/a; WarrantyStartDate: 1900-12-31T23:59:59

# IfcWallStandardCase: Basic Wall:PGR_AnticColonial_WoodFibreBoards_Residence_Utah-193x1380mm-100201410, Basic Wall:PGR_AnticColonial_WoodFibreBoards_Residence_Utah-193x1380mm-100201410:211538
In: Level 1
Type - PredefinedType: STANDARD; Material: PGR_AnticColonial_WoodFibreBoards_Residence_Utah-193x1380mm-100201410 8 mm
Type - NBS_General - Author: Porcelanosa Group; BIMObjectName: PGR_AnticColonial_WoodFibreBoards_Residence_Nogal_193x1380mm-100202966; ManufacturerURL: www.anticcolonial.com; NBSDescription: Wood laminate strips and boards; NBSReference: 45-45-95/370; ProductInformation: http://calidad.info-grupo.com:8081/GeneraFicha3/PDF?articulo=100202966&lang=EN&un=0; Revision: n/a; Uniclass2015Code: Pr_25_71_97_92; Uniclass2015Title: Wood fibre boards; Uniclass2015Version: V1_9; Version: 1
Type - COBie - AccessibilityPerformance: See ProductInformation for technical PDF; AssetType: Fixed; Category: Pr_25_71_97_92: Wood Fibre Boards; CodePerformance: FSC; Color: Walnut; Constituents: n/a; Description: Laminate flooring, RESIDENCE collection from L'ANTIC COLONIAL (Porcelanosa Group), ROBLE DECAPE model and LIFE finish, 19,3x138 cm. (8mm thickness), Class 23/32, abrasion resistance AC4, formed by high density fiber board and water-repellent glues.; DurationUnit: year; ExpectedLife: n/a; Features: See ProductInformation for technical PDF; Grade: n/a; Manufacturer: bim.gp@porcelanosagrupo.com; ModelNumber: 100202966; ModelReference: AC4 RESIDENCE ANTI 1L NOGAL 19,3X138X0,8; Name: WoodFibreBoards_Residence_Nogal_193x1380mm-100202966; ReplacementCost: n/a; Shape: Rectangular; Size: 193x1380x8mm; Sustainability Performance: See ProductInformation for technical PDF; WarrantyDescription: Manufacturer warranty, applicable worldwide, with the pertinent national legislation prevailing in all cases; all products must have been manufactured and fitted in accordance with the Fabricator's Manual, and have been used and cared for in accordance with the Guide to Use, Cleaning and Care available on the web page www.porcelanosa.com; WarrantyDurationLabor: n/a; WarrantyDurationParts: 20; WarrantyDurationUnit: year; WarrantyGuarantorLabor: n/a; WarrantyGuarantorParts: bim.gp@porcelanosagrupo.com
Type - Pset_CoveringCommon - IsExternal: no; Reference: -; AcousticRating: n/a; Finish: Life; FireRating: Cfl-s1; FlammabilityRating: n/a; FragilityRating: n/a; Material: High-density fibreboard; SurfaceSpreadOfFlame: n/a; ThermalTransmittance: 287.5 kg/K/s3; TotalThickness: 8 mm
Type - IFC - IfcExportAS: IfcCoveringType; IfcExportType: Flooring
Type - NBS_Data - AbrasionResistance: AC4; Collection: Residence; CreationDate: 2018/09; SlipResistanceValuePendulumTestValue: Class DS; StainResistance: Grade 5 (G 1 and 2) and Grade 4 (G 3)
COBie - AssetIdentifier: n/a; BarCode: n/a; InstallationDate: 1900-12-31T23:59:59; TagNumber: n/a; WarrantyStartDate: 1900-12-31T23:59:59

# IfcWallStandardCase: Basic Wall:PGR_AnticColonial_WoodFibreBoards_Residence_Vermont-193x1380mm-100176289, Basic Wall:PGR_AnticColonial_WoodFibreBoards_Residence_Vermont-193x1380mm-100176289:211578
In: Level 1
Type - PredefinedType: STANDARD; Material: PGR_AnticColonial_WoodFibreBoards_Residence_Vermont-193x1380mm-100176289 8 mm
Type - NBS_General - Author: Porcelanosa Group; BIMObjectName: PGR_AnticColonial_WoodFibreBoards_Residence_Vermont_193x1380mm-100176289; ManufacturerURL: www.anticcolonial.com; NBSDescription: Wood laminate strips and boards; NBSReference: 45-45-95/370; ProductInformation: http://calidad.info-grupo.com:8081/GeneraFicha3/PDF?articulo=100176289&lang=EN&un=0; Revision: n/a; Uniclass2015Code: Pr_25_71_97_92; Uniclass2015Title: Wood fibre boards; Uniclass2015Version: V1_9; Version: 1
Type - COBie - AccessibilityPerformance: See ProductInformation for technical PDF; AssetType: Fixed; Category: Walls; CodePerformance: FSC; Color: Brown; Constituents: n/a; Description: Laminate flooring, RESIDENCE collection from L'ANTIC COLONIAL (Porcelanosa Group), ROBLE DECAPE model and LIFE finish, 19,3x138 cm. (8mm thickness), Class 23/32, abrasion resistance AC4, formed by high density fiber board and water-repellent glues.; DurationUnit: year; ExpectedLife: n/a; Features: See ProductInformation for technical PDF; Grade: n/a; Manufacturer: bim.gp@porcelanosagrupo.com; ModelNumber: 100176289; ModelReference: AC4 RESIDENCE ANTI 1L VERMONT 19,3X138X0,8; Name: WoodFibreBoards_Residence_Vermont_193x1380mm-100176289; ReplacementCost: n/a; Shape: Rectangular; Size: 193x1380x8mm; Sustainability Performance: See ProductInformation for technical PDF; WarrantyDescription: Manufacturer warranty, applicable worldwide, with the pertinent national legislation prevailing in all cases; all products must have been manufactured and fitted in accordance with the Fabricator's Manual, and have been used and cared for in accordance with the Guide to Use, Cleaning and Care available on the web page www.porcelanosa.com; WarrantyDurationLabor: n/a; WarrantyDurationParts: 20; WarrantyDurationUnit: year; WarrantyGuarantorLabor: n/a; WarrantyGuarantorParts: bim.gp@porcelanosagrupo.com
Type - Pset_CoveringCommon - IsExternal: no; Reference: -; AcousticRating: n/a; Finish: Life; FireRating: Cfl-s1; FlammabilityRating: n/a; FragilityRating: n/a; Material: High-density fibreboard; SurfaceSpreadOfFlame: n/a; ThermalTransmittance: 287.5 kg/K/s3; TotalThickness: 8 mm
Type - IFC - IfcExportAS: IfcCoveringType; IfcExportType: Flooring
Type - NBS_Data - AbrasionResistance: AC4; Collection: Residence; CreationDate: 2018/09; SlipResistanceValuePendulumTestValue: Class DS; StainResistance: Grade 5 (G 1 and 2) and Grade 4 (G 3)
COBie - AssetIdentifier: n/a; BarCode: n/a; InstallationDate: 1900-12-31T23:59:59; TagNumber: n/a; WarrantyStartDate: 1900-12-31T23:59:59

# IfcWallStandardCase: Basic Wall:PGR_AnticColonial_WoodFibreBoards_Residence_Virginia-193x1380mm-100175398, Basic Wall:PGR_AnticColonial_WoodFibreBoards_Residence_Virginia-193x1380mm-100175398:211588
In: Level 1
Type - PredefinedType: STANDARD; Material: PGR_AnticColonial_WoodFibreBoards_Residence_Virginia-193x1380mm-100175398 8 mm
Type - NBS_General - Author: Porcelanosa Group; BIMObjectName: PGR_AnticColonial_WoodFibreBoards_Residence_Virginia_193x1380mm-100175398; ManufacturerURL: www.anticcolonial.com; NBSDescription: Wood laminate strips and boards; NBSReference: 45-45-95/370; ProductInformation: http://calidad.info-grupo.com:8081/GeneraFicha3/PDF?articulo=100175398&lang=EN&un=0; Revision: n/a; Uniclass2015Code: Pr_25_71_97_92; Uniclass2015Title: Wood fibre boards; Uniclass2015Version: V1_9; Version: 1
Type - COBie - AccessibilityPerformance: See ProductInformation for technical PDF; AssetType: Fixed; Category: Walls; CodePerformance: FSC; Color: Sand; Constituents: n/a; Description: Laminate flooring, RESIDENCE collection from L'ANTIC COLONIAL (Porcelanosa Group), ROBLE DECAPE model and LIFE finish, 19,3x138 cm. (8mm thickness), Class 23/32, abrasion resistance AC4, formed by high density fiber board and water-repellent glues.; DurationUnit: year; ExpectedLife: n/a; Features: See ProductInformation for technical PDF; Grade: n/a; Manufacturer: bim.gp@porcelanosagrupo.com; ModelNumber: 100175398; ModelReference: AC4 RESIDENCE ANTI 1L VIRGINIA 19,3X138X0,8; Name: WoodFibreBoards_Residence_Virginia_193x1380mm-100175398; ReplacementCost: n/a; Shape: Rectangular; Size: 193x1380x8mm; Sustainability Performance: See ProductInformation for technical PDF; WarrantyDescription: Manufacturer warranty, applicable worldwide, with the pertinent national legislation prevailing in all cases; all products must have been manufactured and fitted in accordance with the Fabricator's Manual, and have been used and cared for in accordance with the Guide to Use, Cleaning and Care available on the web page www.porcelanosa.com; WarrantyDurationLabor: n/a; WarrantyDurationParts: 20; WarrantyDurationUnit: year; WarrantyGuarantorLabor: n/a; WarrantyGuarantorParts: bim.gp@porcelanosagrupo.com
Type - Pset_CoveringCommon - IsExternal: no; Reference: -; AcousticRating: n/a; Finish: Life; FireRating: Cfl-s1; FlammabilityRating: n/a; FragilityRating: n/a; Material: High-density fibreboard; SurfaceSpreadOfFlame: n/a; ThermalTransmittance: 287.5 kg/K/s3; TotalThickness: 8 mm
Type - IFC - IfcExportAS: IfcCoveringType; IfcExportType: Flooring
Type - NBS_Data - AbrasionResistance: AC4; Collection: Residence; CreationDate: 2018/09; SlipResistanceValuePendulumTestValue: Class DS; StainResistance: Grade 5 (G 1 and 2) and Grade 4 (G 3)
COBie - AssetIdentifier: n/a; BarCode: n/a; InstallationDate: 1900-12-31T23:59:59; TagNumber: n/a; WarrantyStartDate: 1900-12-31T23:59:59
